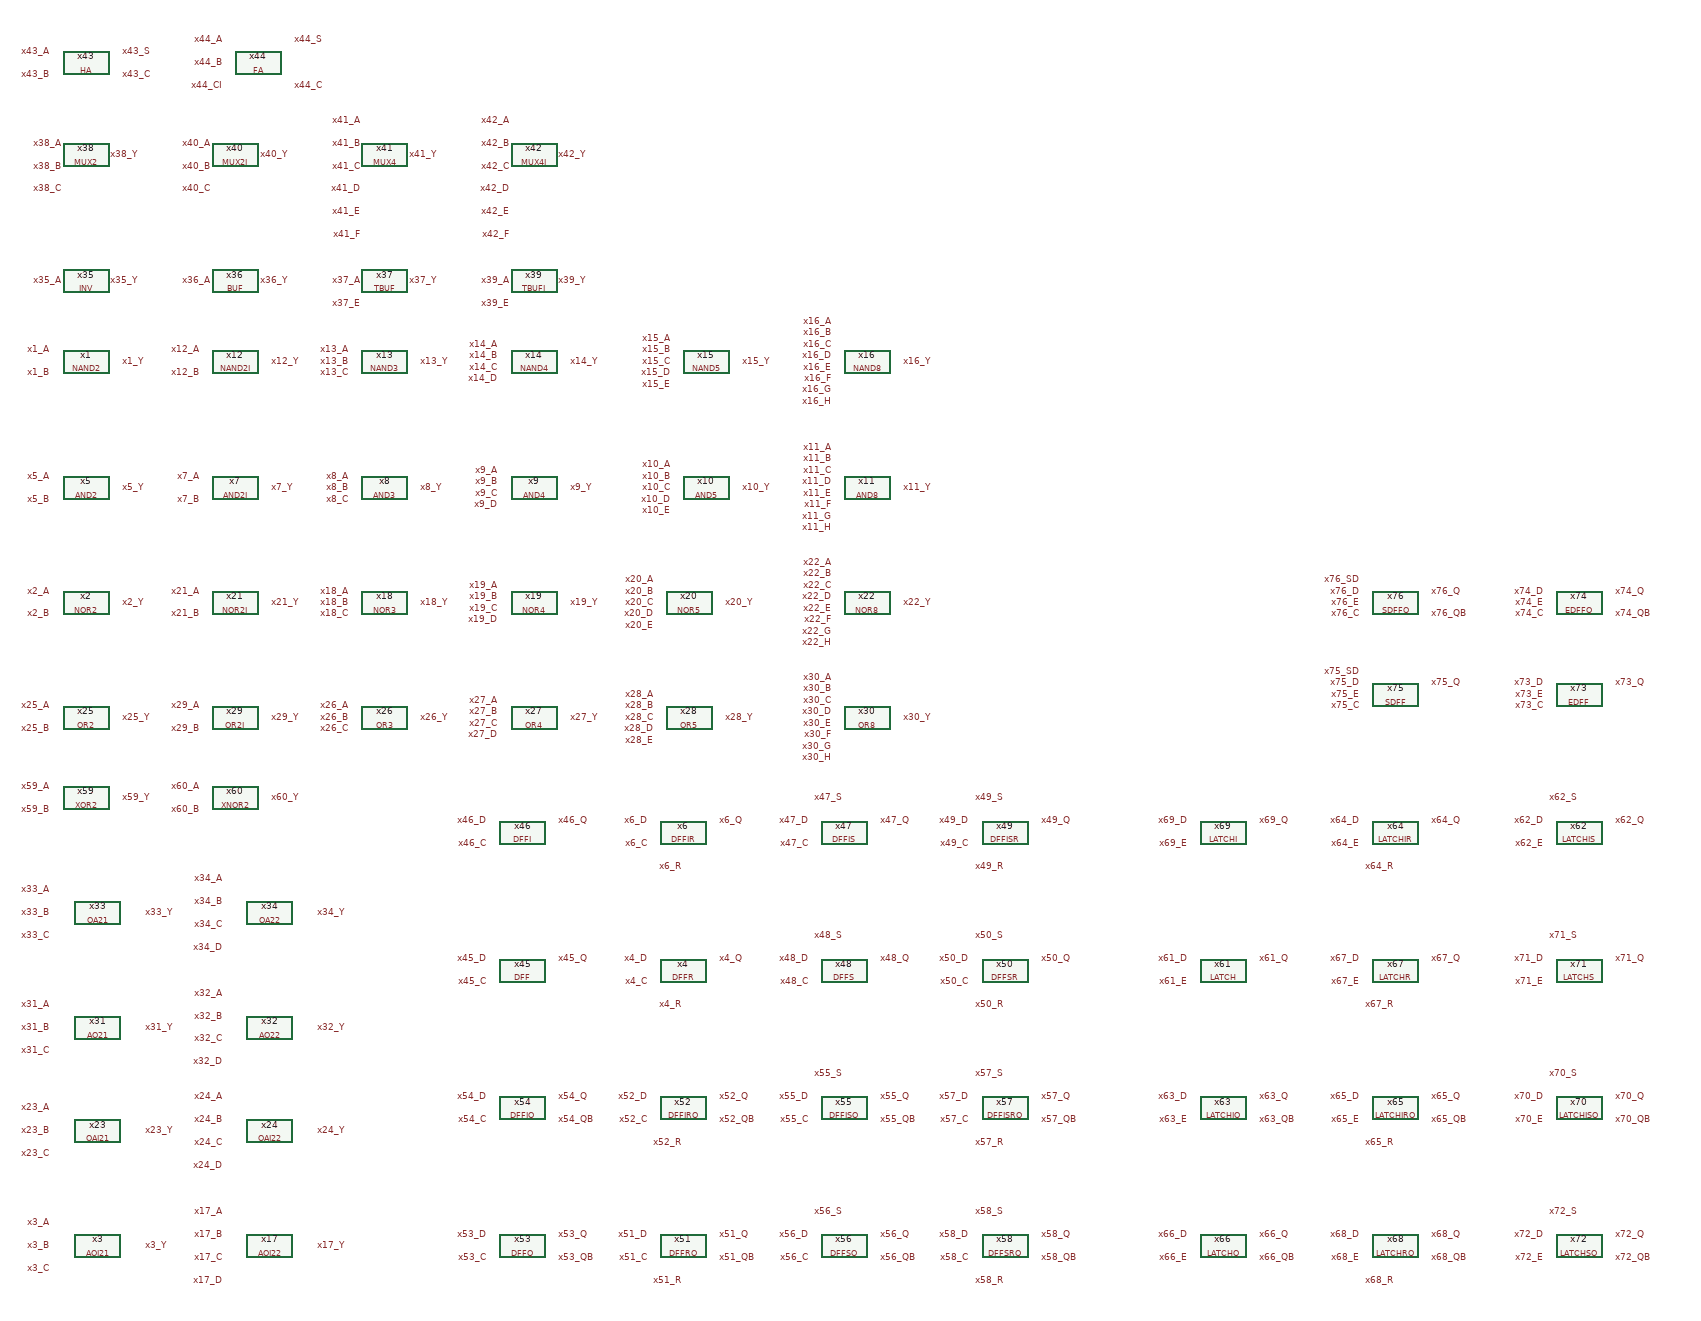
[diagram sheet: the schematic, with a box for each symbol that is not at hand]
v {xschem version=2.9.7 file_version=1.2}
G {}
V {}
S {}
E {}
C {NAND2.sym} 140 -1720 0 0 {name=x1 VCCPIN=VCC VSSPIN=VSS}
C {NOR2.sym} 140 -1300 0 0 {name=x2 VCCPIN=VCC VSSPIN=VSS}
C {AOI21.sym} 160 -180 0 0 {name=x3 VCCPIN=VCC VSSPIN=VSS}
C {DFFR.sym} 1180 -660 0 0 {name=x4 VCCPIN=VCC VSSPIN=VSS}
C {AND2.sym} 140 -1500 0 0 {name=x5 VCCPIN=VCC VSSPIN=VSS}
C {DFFIR.sym} 1180 -900 0 0 {name=x6 VCCPIN=VCC VSSPIN=VSS}
C {AND2I.sym} 400 -1500 0 0 {name=x7 VCCPIN=VCC VSSPIN=VSS}
C {AND3.sym} 660 -1500 0 0 {name=x8 VCCPIN=VCC VSSPIN=VSS}
C {AND4.sym} 920 -1500 0 0 {name=x9 VCCPIN=VCC VSSPIN=VSS}
C {AND5.sym} 1220 -1500 0 0 {name=x10 VCCPIN=VCC VSSPIN=VSS}
C {AND8.sym} 1500 -1500 0 0 {name=x11 VCCPIN=VCC VSSPIN=VSS}
C {NAND2I.sym} 400 -1720 0 0 {name=x12 VCCPIN=VCC VSSPIN=VSS}
C {NAND3.sym} 660 -1720 0 0 {name=x13 VCCPIN=VCC VSSPIN=VSS}
C {NAND4.sym} 920 -1720 0 0 {name=x14 VCCPIN=VCC VSSPIN=VSS}
C {NAND5.sym} 1220 -1720 0 0 {name=x15 VCCPIN=VCC VSSPIN=VSS}
C {NAND8.sym} 1500 -1720 0 0 {name=x16 VCCPIN=VCC VSSPIN=VSS}
C {AOI22.sym} 460 -180 0 0 {name=x17 VCCPIN=VCC VSSPIN=VSS}
C {NOR3.sym} 660 -1300 0 0 {name=x18 VCCPIN=VCC VSSPIN=VSS}
C {NOR4.sym} 920 -1300 0 0 {name=x19 VCCPIN=VCC VSSPIN=VSS}
C {NOR5.sym} 1190 -1300 0 0 {name=x20 VCCPIN=VCC VSSPIN=VSS}
C {NOR2I.sym} 400 -1300 0 0 {name=x21 VCCPIN=VCC VSSPIN=VSS}
C {NOR8.sym} 1500 -1300 0 0 {name=x22 VCCPIN=VCC VSSPIN=VSS}
C {OAI21.sym} 160 -380 0 0 {name=x23 VCCPIN=VCC VSSPIN=VSS}
C {OAI22.sym} 460 -380 0 0 {name=x24 VCCPIN=VCC VSSPIN=VSS}
C {OR2.sym} 140 -1100 0 0 {name=x25 VCCPIN=VCC VSSPIN=VSS}
C {OR3.sym} 660 -1100 0 0 {name=x26 VCCPIN=VCC VSSPIN=VSS}
C {OR4.sym} 920 -1100 0 0 {name=x27 VCCPIN=VCC VSSPIN=VSS}
C {OR5.sym} 1190 -1100 0 0 {name=x28 VCCPIN=VCC VSSPIN=VSS}
C {OR2I.sym} 400 -1100 0 0 {name=x29 VCCPIN=VCC VSSPIN=VSS}
C {OR8.sym} 1500 -1100 0 0 {name=x30 VCCPIN=VCC VSSPIN=VSS}
C {AO21.sym} 160 -560 0 0 {name=x31 VCCPIN=VCC VSSPIN=VSS}
C {AO22.sym} 460 -560 0 0 {name=x32 VCCPIN=VCC VSSPIN=VSS}
C {OA21.sym} 160 -760 0 0 {name=x33 VCCPIN=VCC VSSPIN=VSS}
C {OA22.sym} 460 -760 0 0 {name=x34 VCCPIN=VCC VSSPIN=VSS}
C {INV.sym} 140 -1860 0 0 {name=x35 VCCPIN=VCC VSSPIN=VSS}
C {BUF.sym} 400 -1860 0 0 {name=x36 VCCPIN=VCC VSSPIN=VSS}
C {TBUF.sym} 660 -1860 0 0 {name=x37 VCCPIN=VCC VSSPIN=VSS}
C {TBUFI.sym} 920 -1860 0 0 {name=x39 VCCPIN=VCC VSSPIN=VSS}
C {MUX2.sym} 140 -2080 0 0 {name=x38 VCCPIN=VCC VSSPIN=VSS}
C {MUX2I.sym} 400 -2080 0 0 {name=x40 VCCPIN=VCC VSSPIN=VSS}
C {MUX4.sym} 660 -2080 0 0 {name=x41 VCCPIN=VCC VSSPIN=VSS}
C {MUX4I.sym} 920 -2080 0 0 {name=x42 VCCPIN=VCC VSSPIN=VSS}
C {HA.sym} 140 -2240 0 0 {name=x43 VCCPIN=VCC VSSPIN=VSS}
C {FA.sym} 440 -2240 0 0 {name=x44 VCCPIN=VCC VSSPIN=VSS}
C {DFF.sym} 900 -660 0 0 {name=x45 VCCPIN=VCC VSSPIN=VSS}
C {DFFI.sym} 900 -900 0 0 {name=x46 VCCPIN=VCC VSSPIN=VSS}
C {DFFIS.sym} 1460 -900 0 0 {name=x47 VCCPIN=VCC VSSPIN=VSS}
C {DFFS.sym} 1460 -660 0 0 {name=x48 VCCPIN=VCC VSSPIN=VSS}
C {DFFISR.sym} 1740 -900 0 0 {name=x49 VCCPIN=VCC VSSPIN=VSS}
C {DFFSR.sym} 1740 -660 0 0 {name=x50 VCCPIN=VCC VSSPIN=VSS}
C {DFFRQ.sym} 1180 -180 0 0 {name=x51 VCCPIN=VCC VSSPIN=VSS}
C {DFFIRQ.sym} 1180 -420 0 0 {name=x52 VCCPIN=VCC VSSPIN=VSS}
C {DFFQ.sym} 900 -180 0 0 {name=x53 VCCPIN=VCC VSSPIN=VSS}
C {DFFIQ.sym} 900 -420 0 0 {name=x54 VCCPIN=VCC VSSPIN=VSS}
C {DFFISQ.sym} 1460 -420 0 0 {name=x55 VCCPIN=VCC VSSPIN=VSS}
C {DFFSQ.sym} 1460 -180 0 0 {name=x56 VCCPIN=VCC VSSPIN=VSS}
C {DFFISRQ.sym} 1740 -420 0 0 {name=x57 VCCPIN=VCC VSSPIN=VSS}
C {DFFSRQ.sym} 1740 -180 0 0 {name=x58 VCCPIN=VCC VSSPIN=VSS}
C {XOR2.sym} 140 -960 0 0 {name=x59 VCCPIN=VCC VSSPIN=VSS}
C {XNOR2.sym} 400 -960 0 0 {name=x60 VCCPIN=VCC VSSPIN=VSS}
C {LATCH.sym} 2120 -660 0 0 {name=x61 VCCPIN=VCC VSSPIN=VSS}
C {LATCHIQ.sym} 2120 -420 0 0 {name=x63 VCCPIN=VCC VSSPIN=VSS}
C {LATCHIR.sym} 2420 -900 0 0 {name=x64 VCCPIN=VCC VSSPIN=VSS}
C {LATCHIRQ.sym} 2420 -420 0 0 {name=x65 VCCPIN=VCC VSSPIN=VSS}
C {LATCHQ.sym} 2120 -180 0 0 {name=x66 VCCPIN=VCC VSSPIN=VSS}
C {LATCHR.sym} 2420 -660 0 0 {name=x67 VCCPIN=VCC VSSPIN=VSS}
C {LATCHRQ.sym} 2420 -180 0 0 {name=x68 VCCPIN=VCC VSSPIN=VSS}
C {LATCHI.sym} 2120 -900 0 0 {name=x69 VCCPIN=VCC VSSPIN=VSS}
C {LATCHIS.sym} 2740 -900 0 0 {name=x62 VCCPIN=VCC VSSPIN=VSS}
C {LATCHISQ.sym} 2740 -420 0 0 {name=x70 VCCPIN=VCC VSSPIN=VSS}
C {LATCHS.sym} 2740 -660 0 0 {name=x71 VCCPIN=VCC VSSPIN=VSS}
C {LATCHSQ.sym} 2740 -180 0 0 {name=x72 VCCPIN=VCC VSSPIN=VSS}
C {EDFF.sym} 2740 -1140 0 0 {name=x73 VCCPIN=VCC VSSPIN=VSS}
C {EDFFQ.sym} 2740 -1300 0 0 {name=x74 VCCPIN=VCC VSSPIN=VSS}
C {SDFF.sym} 2420 -1140 0 0 {name=x75 VCCPIN=VCC VSSPIN=VSS}
C {SDFFQ.sym} 2420 -1300 0 0 {name=x76 VCCPIN=VCC VSSPIN=VSS}
C {title.sym} 160 -30 0 0 {name=l1 author="Stefan Schippers"}
C {lab_pin.sym} 200 -1720 0 1 {name=p1 lab=x1_Y}
C {lab_pin.sym} 80 -1740 0 0 {name=p2 lab=x1_A}
C {lab_pin.sym} 80 -1700 0 0 {name=p3 lab=x1_B}
C {lab_pin.sym} 200 -1300 0 1 {name=p4 lab=x2_Y}
C {lab_pin.sym} 80 -1320 0 0 {name=p5 lab=x2_A}
C {lab_pin.sym} 80 -1280 0 0 {name=p6 lab=x2_B}
C {lab_pin.sym} 240 -180 0 1 {name=p7 lab=x3_Y}
C {lab_pin.sym} 80 -220 0 0 {name=p8 lab=x3_A}
C {lab_pin.sym} 80 -180 0 0 {name=p9 lab=x3_B}
C {lab_pin.sym} 80 -140 0 0 {name=p10 lab=x3_C}
C {lab_pin.sym} 1240 -680 0 1 {name=p11 lab=x4_Q}
C {lab_pin.sym} 1120 -680 0 0 {name=p12 lab=x4_D}
C {lab_pin.sym} 1120 -640 0 0 {name=p13 lab=x4_C}
C {lab_pin.sym} 1180 -600 0 0 {name=p14 lab=x4_R}
C {lab_pin.sym} 200 -1500 0 1 {name=p15 lab=x5_Y}
C {lab_pin.sym} 80 -1520 0 0 {name=p16 lab=x5_A}
C {lab_pin.sym} 80 -1480 0 0 {name=p17 lab=x5_B}
C {lab_pin.sym} 1240 -920 0 1 {name=p18 lab=x6_Q}
C {lab_pin.sym} 1120 -920 0 0 {name=p19 lab=x6_D}
C {lab_pin.sym} 1120 -880 0 0 {name=p20 lab=x6_C}
C {lab_pin.sym} 1180 -840 0 0 {name=p21 lab=x6_R}
C {lab_pin.sym} 460 -1500 0 1 {name=p22 lab=x7_Y}
C {lab_pin.sym} 340 -1520 0 0 {name=p23 lab=x7_A}
C {lab_pin.sym} 340 -1480 0 0 {name=p24 lab=x7_B}
C {lab_pin.sym} 720 -1500 0 1 {name=p25 lab=x8_Y}
C {lab_pin.sym} 600 -1520 0 0 {name=p26 lab=x8_A}
C {lab_pin.sym} 600 -1500 0 0 {name=p27 lab=x8_B}
C {lab_pin.sym} 600 -1480 0 0 {name=p28 lab=x8_C}
C {lab_pin.sym} 980 -1500 0 1 {name=p29 lab=x9_Y}
C {lab_pin.sym} 860 -1530 0 0 {name=p30 lab=x9_A}
C {lab_pin.sym} 860 -1510 0 0 {name=p31 lab=x9_B}
C {lab_pin.sym} 860 -1490 0 0 {name=p32 lab=x9_C}
C {lab_pin.sym} 860 -1470 0 0 {name=p33 lab=x9_D}
C {lab_pin.sym} 1280 -1500 0 1 {name=p34 lab=x10_Y}
C {lab_pin.sym} 1160 -1540 0 0 {name=p35 lab=x10_A}
C {lab_pin.sym} 1160 -1520 0 0 {name=p36 lab=x10_B}
C {lab_pin.sym} 1160 -1500 0 0 {name=p37 lab=x10_C}
C {lab_pin.sym} 1160 -1480 0 0 {name=p38 lab=x10_D}
C {lab_pin.sym} 1160 -1460 0 0 {name=p39 lab=x10_E}
C {lab_pin.sym} 1560 -1500 0 1 {name=p40 lab=x11_Y}
C {lab_pin.sym} 1440 -1570 0 0 {name=p41 lab=x11_A}
C {lab_pin.sym} 1440 -1550 0 0 {name=p42 lab=x11_B}
C {lab_pin.sym} 1440 -1530 0 0 {name=p43 lab=x11_C}
C {lab_pin.sym} 1440 -1510 0 0 {name=p44 lab=x11_D}
C {lab_pin.sym} 1440 -1490 0 0 {name=p45 lab=x11_E}
C {lab_pin.sym} 1440 -1470 0 0 {name=p46 lab=x11_F}
C {lab_pin.sym} 1440 -1450 0 0 {name=p47 lab=x11_G}
C {lab_pin.sym} 1440 -1430 0 0 {name=p48 lab=x11_H}
C {lab_pin.sym} 460 -1720 0 1 {name=p49 lab=x12_Y}
C {lab_pin.sym} 340 -1740 0 0 {name=p50 lab=x12_A}
C {lab_pin.sym} 340 -1700 0 0 {name=p51 lab=x12_B}
C {lab_pin.sym} 720 -1720 0 1 {name=p52 lab=x13_Y}
C {lab_pin.sym} 600 -1740 0 0 {name=p53 lab=x13_A}
C {lab_pin.sym} 600 -1720 0 0 {name=p54 lab=x13_B}
C {lab_pin.sym} 600 -1700 0 0 {name=p55 lab=x13_C}
C {lab_pin.sym} 980 -1720 0 1 {name=p56 lab=x14_Y}
C {lab_pin.sym} 860 -1750 0 0 {name=p57 lab=x14_A}
C {lab_pin.sym} 860 -1730 0 0 {name=p58 lab=x14_B}
C {lab_pin.sym} 860 -1710 0 0 {name=p59 lab=x14_C}
C {lab_pin.sym} 860 -1690 0 0 {name=p60 lab=x14_D}
C {lab_pin.sym} 1280 -1720 0 1 {name=p61 lab=x15_Y}
C {lab_pin.sym} 1160 -1760 0 0 {name=p62 lab=x15_A}
C {lab_pin.sym} 1160 -1740 0 0 {name=p63 lab=x15_B}
C {lab_pin.sym} 1160 -1720 0 0 {name=p64 lab=x15_C}
C {lab_pin.sym} 1160 -1700 0 0 {name=p65 lab=x15_D}
C {lab_pin.sym} 1160 -1680 0 0 {name=p66 lab=x15_E}
C {lab_pin.sym} 1560 -1720 0 1 {name=p67 lab=x16_Y}
C {lab_pin.sym} 1440 -1790 0 0 {name=p68 lab=x16_A}
C {lab_pin.sym} 1440 -1770 0 0 {name=p69 lab=x16_B}
C {lab_pin.sym} 1440 -1750 0 0 {name=p70 lab=x16_C}
C {lab_pin.sym} 1440 -1730 0 0 {name=p71 lab=x16_D}
C {lab_pin.sym} 1440 -1710 0 0 {name=p72 lab=x16_E}
C {lab_pin.sym} 1440 -1690 0 0 {name=p73 lab=x16_F}
C {lab_pin.sym} 1440 -1670 0 0 {name=p74 lab=x16_G}
C {lab_pin.sym} 1440 -1650 0 0 {name=p75 lab=x16_H}
C {lab_pin.sym} 540 -180 0 1 {name=p76 lab=x17_Y}
C {lab_pin.sym} 380 -240 0 0 {name=p77 lab=x17_A}
C {lab_pin.sym} 380 -200 0 0 {name=p78 lab=x17_B}
C {lab_pin.sym} 380 -160 0 0 {name=p79 lab=x17_C}
C {lab_pin.sym} 380 -120 0 0 {name=p80 lab=x17_D}
C {lab_pin.sym} 720 -1300 0 1 {name=p81 lab=x18_Y}
C {lab_pin.sym} 600 -1320 0 0 {name=p82 lab=x18_A}
C {lab_pin.sym} 600 -1300 0 0 {name=p83 lab=x18_B}
C {lab_pin.sym} 600 -1280 0 0 {name=p84 lab=x18_C}
C {lab_pin.sym} 980 -1300 0 1 {name=p85 lab=x19_Y}
C {lab_pin.sym} 860 -1330 0 0 {name=p86 lab=x19_A}
C {lab_pin.sym} 860 -1310 0 0 {name=p87 lab=x19_B}
C {lab_pin.sym} 860 -1290 0 0 {name=p88 lab=x19_C}
C {lab_pin.sym} 860 -1270 0 0 {name=p89 lab=x19_D}
C {lab_pin.sym} 1250 -1300 0 1 {name=p90 lab=x20_Y}
C {lab_pin.sym} 1130 -1340 0 0 {name=p91 lab=x20_A}
C {lab_pin.sym} 1130 -1320 0 0 {name=p92 lab=x20_B}
C {lab_pin.sym} 1130 -1300 0 0 {name=p93 lab=x20_C}
C {lab_pin.sym} 1130 -1280 0 0 {name=p94 lab=x20_D}
C {lab_pin.sym} 1130 -1260 0 0 {name=p95 lab=x20_E}
C {lab_pin.sym} 460 -1300 0 1 {name=p96 lab=x21_Y}
C {lab_pin.sym} 340 -1320 0 0 {name=p97 lab=x21_A}
C {lab_pin.sym} 340 -1280 0 0 {name=p98 lab=x21_B}
C {lab_pin.sym} 1560 -1300 0 1 {name=p99 lab=x22_Y}
C {lab_pin.sym} 1440 -1370 0 0 {name=p100 lab=x22_A}
C {lab_pin.sym} 1440 -1350 0 0 {name=p101 lab=x22_B}
C {lab_pin.sym} 1440 -1330 0 0 {name=p102 lab=x22_C}
C {lab_pin.sym} 1440 -1310 0 0 {name=p103 lab=x22_D}
C {lab_pin.sym} 1440 -1290 0 0 {name=p104 lab=x22_E}
C {lab_pin.sym} 1440 -1270 0 0 {name=p105 lab=x22_F}
C {lab_pin.sym} 1440 -1250 0 0 {name=p106 lab=x22_G}
C {lab_pin.sym} 1440 -1230 0 0 {name=p107 lab=x22_H}
C {lab_pin.sym} 240 -380 0 1 {name=p108 lab=x23_Y}
C {lab_pin.sym} 80 -420 0 0 {name=p109 lab=x23_A}
C {lab_pin.sym} 80 -380 0 0 {name=p110 lab=x23_B}
C {lab_pin.sym} 80 -340 0 0 {name=p111 lab=x23_C}
C {lab_pin.sym} 540 -380 0 1 {name=p112 lab=x24_Y}
C {lab_pin.sym} 380 -440 0 0 {name=p113 lab=x24_A}
C {lab_pin.sym} 380 -400 0 0 {name=p114 lab=x24_B}
C {lab_pin.sym} 380 -360 0 0 {name=p115 lab=x24_C}
C {lab_pin.sym} 380 -320 0 0 {name=p116 lab=x24_D}
C {lab_pin.sym} 200 -1100 0 1 {name=p117 lab=x25_Y}
C {lab_pin.sym} 80 -1120 0 0 {name=p118 lab=x25_A}
C {lab_pin.sym} 80 -1080 0 0 {name=p119 lab=x25_B}
C {lab_pin.sym} 720 -1100 0 1 {name=p120 lab=x26_Y}
C {lab_pin.sym} 600 -1120 0 0 {name=p121 lab=x26_A}
C {lab_pin.sym} 600 -1100 0 0 {name=p122 lab=x26_B}
C {lab_pin.sym} 600 -1080 0 0 {name=p123 lab=x26_C}
C {lab_pin.sym} 980 -1100 0 1 {name=p124 lab=x27_Y}
C {lab_pin.sym} 860 -1130 0 0 {name=p125 lab=x27_A}
C {lab_pin.sym} 860 -1110 0 0 {name=p126 lab=x27_B}
C {lab_pin.sym} 860 -1090 0 0 {name=p127 lab=x27_C}
C {lab_pin.sym} 860 -1070 0 0 {name=p128 lab=x27_D}
C {lab_pin.sym} 1250 -1100 0 1 {name=p129 lab=x28_Y}
C {lab_pin.sym} 1130 -1140 0 0 {name=p130 lab=x28_A}
C {lab_pin.sym} 1130 -1120 0 0 {name=p131 lab=x28_B}
C {lab_pin.sym} 1130 -1100 0 0 {name=p132 lab=x28_C}
C {lab_pin.sym} 1130 -1080 0 0 {name=p133 lab=x28_D}
C {lab_pin.sym} 1130 -1060 0 0 {name=p134 lab=x28_E}
C {lab_pin.sym} 460 -1100 0 1 {name=p135 lab=x29_Y}
C {lab_pin.sym} 340 -1120 0 0 {name=p136 lab=x29_A}
C {lab_pin.sym} 340 -1080 0 0 {name=p137 lab=x29_B}
C {lab_pin.sym} 1560 -1100 0 1 {name=p138 lab=x30_Y}
C {lab_pin.sym} 1440 -1170 0 0 {name=p139 lab=x30_A}
C {lab_pin.sym} 1440 -1150 0 0 {name=p140 lab=x30_B}
C {lab_pin.sym} 1440 -1130 0 0 {name=p141 lab=x30_C}
C {lab_pin.sym} 1440 -1110 0 0 {name=p142 lab=x30_D}
C {lab_pin.sym} 1440 -1090 0 0 {name=p143 lab=x30_E}
C {lab_pin.sym} 1440 -1070 0 0 {name=p144 lab=x30_F}
C {lab_pin.sym} 1440 -1050 0 0 {name=p145 lab=x30_G}
C {lab_pin.sym} 1440 -1030 0 0 {name=p146 lab=x30_H}
C {lab_pin.sym} 240 -560 0 1 {name=p147 lab=x31_Y}
C {lab_pin.sym} 80 -600 0 0 {name=p148 lab=x31_A}
C {lab_pin.sym} 80 -560 0 0 {name=p149 lab=x31_B}
C {lab_pin.sym} 80 -520 0 0 {name=p150 lab=x31_C}
C {lab_pin.sym} 540 -560 0 1 {name=p151 lab=x32_Y}
C {lab_pin.sym} 380 -620 0 0 {name=p152 lab=x32_A}
C {lab_pin.sym} 380 -580 0 0 {name=p153 lab=x32_B}
C {lab_pin.sym} 380 -540 0 0 {name=p154 lab=x32_C}
C {lab_pin.sym} 380 -500 0 0 {name=p155 lab=x32_D}
C {lab_pin.sym} 240 -760 0 1 {name=p156 lab=x33_Y}
C {lab_pin.sym} 80 -800 0 0 {name=p157 lab=x33_A}
C {lab_pin.sym} 80 -760 0 0 {name=p158 lab=x33_B}
C {lab_pin.sym} 80 -720 0 0 {name=p159 lab=x33_C}
C {lab_pin.sym} 540 -760 0 1 {name=p160 lab=x34_Y}
C {lab_pin.sym} 380 -820 0 0 {name=p161 lab=x34_A}
C {lab_pin.sym} 380 -780 0 0 {name=p162 lab=x34_B}
C {lab_pin.sym} 380 -740 0 0 {name=p163 lab=x34_C}
C {lab_pin.sym} 380 -700 0 0 {name=p164 lab=x34_D}
C {lab_pin.sym} 180 -1860 0 1 {name=p165 lab=x35_Y}
C {lab_pin.sym} 100 -1860 0 0 {name=p166 lab=x35_A}
C {lab_pin.sym} 440 -1860 0 1 {name=p167 lab=x36_Y}
C {lab_pin.sym} 360 -1860 0 0 {name=p168 lab=x36_A}
C {lab_pin.sym} 700 -1860 0 1 {name=p169 lab=x37_Y}
C {lab_pin.sym} 620 -1860 0 0 {name=p170 lab=x37_A}
C {lab_pin.sym} 620 -1820 0 0 {name=p171 lab=x37_E}
C {lab_pin.sym} 960 -1860 0 1 {name=p172 lab=x39_Y}
C {lab_pin.sym} 880 -1860 0 0 {name=p173 lab=x39_A}
C {lab_pin.sym} 880 -1820 0 0 {name=p174 lab=x39_E}
C {lab_pin.sym} 180 -2080 0 1 {name=p175 lab=x38_Y}
C {lab_pin.sym} 100 -2100 0 0 {name=p176 lab=x38_A}
C {lab_pin.sym} 100 -2060 0 0 {name=p177 lab=x38_B}
C {lab_pin.sym} 100 -2020 0 0 {name=p178 lab=x38_C}
C {lab_pin.sym} 440 -2080 0 1 {name=p179 lab=x40_Y}
C {lab_pin.sym} 360 -2100 0 0 {name=p180 lab=x40_A}
C {lab_pin.sym} 360 -2060 0 0 {name=p181 lab=x40_B}
C {lab_pin.sym} 360 -2020 0 0 {name=p182 lab=x40_C}
C {lab_pin.sym} 700 -2080 0 1 {name=p183 lab=x41_Y}
C {lab_pin.sym} 620 -2140 0 0 {name=p184 lab=x41_A}
C {lab_pin.sym} 620 -2100 0 0 {name=p185 lab=x41_B}
C {lab_pin.sym} 620 -2060 0 0 {name=p186 lab=x41_C}
C {lab_pin.sym} 620 -2020 0 0 {name=p187 lab=x41_D}
C {lab_pin.sym} 620 -1980 0 0 {name=p188 lab=x41_E}
C {lab_pin.sym} 620 -1940 0 0 {name=p189 lab=x41_F}
C {lab_pin.sym} 960 -2080 0 1 {name=p190 lab=x42_Y}
C {lab_pin.sym} 880 -2140 0 0 {name=p191 lab=x42_A}
C {lab_pin.sym} 880 -2100 0 0 {name=p192 lab=x42_B}
C {lab_pin.sym} 880 -2060 0 0 {name=p193 lab=x42_C}
C {lab_pin.sym} 880 -2020 0 0 {name=p194 lab=x42_D}
C {lab_pin.sym} 880 -1980 0 0 {name=p195 lab=x42_E}
C {lab_pin.sym} 880 -1940 0 0 {name=p196 lab=x42_F}
C {lab_pin.sym} 200 -2260 0 1 {name=p197 lab=x43_S}
C {lab_pin.sym} 200 -2220 0 1 {name=p198 lab=x43_C}
C {lab_pin.sym} 80 -2260 0 0 {name=p199 lab=x43_A}
C {lab_pin.sym} 80 -2220 0 0 {name=p200 lab=x43_B}
C {lab_pin.sym} 500 -2280 0 1 {name=p201 lab=x44_S}
C {lab_pin.sym} 500 -2200 0 1 {name=p202 lab=x44_C}
C {lab_pin.sym} 380 -2280 0 0 {name=p203 lab=x44_A}
C {lab_pin.sym} 380 -2240 0 0 {name=p204 lab=x44_B}
C {lab_pin.sym} 380 -2200 0 0 {name=p205 lab=x44_CI}
C {lab_pin.sym} 960 -680 0 1 {name=p206 lab=x45_Q}
C {lab_pin.sym} 840 -680 0 0 {name=p207 lab=x45_D}
C {lab_pin.sym} 840 -640 0 0 {name=p208 lab=x45_C}
C {lab_pin.sym} 960 -920 0 1 {name=p209 lab=x46_Q}
C {lab_pin.sym} 840 -920 0 0 {name=p210 lab=x46_D}
C {lab_pin.sym} 840 -880 0 0 {name=p211 lab=x46_C}
C {lab_pin.sym} 1520 -920 0 1 {name=p212 lab=x47_Q}
C {lab_pin.sym} 1400 -920 0 0 {name=p213 lab=x47_D}
C {lab_pin.sym} 1400 -880 0 0 {name=p214 lab=x47_C}
C {lab_pin.sym} 1460 -960 0 0 {name=p215 lab=x47_S}
C {lab_pin.sym} 1520 -680 0 1 {name=p216 lab=x48_Q}
C {lab_pin.sym} 1400 -680 0 0 {name=p217 lab=x48_D}
C {lab_pin.sym} 1400 -640 0 0 {name=p218 lab=x48_C}
C {lab_pin.sym} 1460 -720 0 0 {name=p219 lab=x48_S}
C {lab_pin.sym} 1800 -920 0 1 {name=p220 lab=x49_Q}
C {lab_pin.sym} 1680 -920 0 0 {name=p221 lab=x49_D}
C {lab_pin.sym} 1680 -880 0 0 {name=p222 lab=x49_C}
C {lab_pin.sym} 1740 -960 0 0 {name=p223 lab=x49_S}
C {lab_pin.sym} 1740 -840 0 0 {name=p224 lab=x49_R}
C {lab_pin.sym} 1800 -680 0 1 {name=p225 lab=x50_Q}
C {lab_pin.sym} 1680 -680 0 0 {name=p226 lab=x50_D}
C {lab_pin.sym} 1680 -640 0 0 {name=p227 lab=x50_C}
C {lab_pin.sym} 1740 -720 0 0 {name=p228 lab=x50_S}
C {lab_pin.sym} 1740 -600 0 0 {name=p229 lab=x50_R}
C {lab_pin.sym} 1240 -200 0 1 {name=p230 lab=x51_Q}
C {lab_pin.sym} 1240 -160 0 1 {name=p231 lab=x51_QB}
C {lab_pin.sym} 1120 -200 0 0 {name=p232 lab=x51_D}
C {lab_pin.sym} 1120 -160 0 0 {name=p233 lab=x51_C}
C {lab_pin.sym} 1180 -120 0 0 {name=p234 lab=x51_R}
C {lab_pin.sym} 1240 -440 0 1 {name=p235 lab=x52_Q}
C {lab_pin.sym} 1240 -400 0 1 {name=p236 lab=x52_QB}
C {lab_pin.sym} 1120 -440 0 0 {name=p237 lab=x52_D}
C {lab_pin.sym} 1120 -400 0 0 {name=p238 lab=x52_C}
C {lab_pin.sym} 1180 -360 0 0 {name=p239 lab=x52_R}
C {lab_pin.sym} 960 -200 0 1 {name=p240 lab=x53_Q}
C {lab_pin.sym} 960 -160 0 1 {name=p241 lab=x53_QB}
C {lab_pin.sym} 840 -200 0 0 {name=p242 lab=x53_D}
C {lab_pin.sym} 840 -160 0 0 {name=p243 lab=x53_C}
C {lab_pin.sym} 960 -440 0 1 {name=p244 lab=x54_Q}
C {lab_pin.sym} 960 -400 0 1 {name=p245 lab=x54_QB}
C {lab_pin.sym} 840 -440 0 0 {name=p246 lab=x54_D}
C {lab_pin.sym} 840 -400 0 0 {name=p247 lab=x54_C}
C {lab_pin.sym} 1520 -440 0 1 {name=p248 lab=x55_Q}
C {lab_pin.sym} 1520 -400 0 1 {name=p249 lab=x55_QB}
C {lab_pin.sym} 1400 -440 0 0 {name=p250 lab=x55_D}
C {lab_pin.sym} 1400 -400 0 0 {name=p251 lab=x55_C}
C {lab_pin.sym} 1460 -480 0 0 {name=p252 lab=x55_S}
C {lab_pin.sym} 1520 -200 0 1 {name=p253 lab=x56_Q}
C {lab_pin.sym} 1520 -160 0 1 {name=p254 lab=x56_QB}
C {lab_pin.sym} 1400 -200 0 0 {name=p255 lab=x56_D}
C {lab_pin.sym} 1400 -160 0 0 {name=p256 lab=x56_C}
C {lab_pin.sym} 1460 -240 0 0 {name=p257 lab=x56_S}
C {lab_pin.sym} 1800 -440 0 1 {name=p258 lab=x57_Q}
C {lab_pin.sym} 1800 -400 0 1 {name=p259 lab=x57_QB}
C {lab_pin.sym} 1680 -440 0 0 {name=p260 lab=x57_D}
C {lab_pin.sym} 1680 -400 0 0 {name=p261 lab=x57_C}
C {lab_pin.sym} 1740 -480 0 0 {name=p262 lab=x57_S}
C {lab_pin.sym} 1740 -360 0 0 {name=p263 lab=x57_R}
C {lab_pin.sym} 1800 -200 0 1 {name=p264 lab=x58_Q}
C {lab_pin.sym} 1800 -160 0 1 {name=p265 lab=x58_QB}
C {lab_pin.sym} 1680 -200 0 0 {name=p266 lab=x58_D}
C {lab_pin.sym} 1680 -160 0 0 {name=p267 lab=x58_C}
C {lab_pin.sym} 1740 -240 0 0 {name=p268 lab=x58_S}
C {lab_pin.sym} 1740 -120 0 0 {name=p269 lab=x58_R}
C {lab_pin.sym} 200 -960 0 1 {name=p270 lab=x59_Y}
C {lab_pin.sym} 80 -980 0 0 {name=p271 lab=x59_A}
C {lab_pin.sym} 80 -940 0 0 {name=p272 lab=x59_B}
C {lab_pin.sym} 460 -960 0 1 {name=p273 lab=x60_Y}
C {lab_pin.sym} 340 -980 0 0 {name=p274 lab=x60_A}
C {lab_pin.sym} 340 -940 0 0 {name=p275 lab=x60_B}
C {lab_pin.sym} 2180 -680 0 1 {name=p276 lab=x61_Q}
C {lab_pin.sym} 2060 -680 0 0 {name=p277 lab=x61_D}
C {lab_pin.sym} 2060 -640 0 0 {name=p278 lab=x61_E}
C {lab_pin.sym} 2180 -440 0 1 {name=p279 lab=x63_Q}
C {lab_pin.sym} 2180 -400 0 1 {name=p280 lab=x63_QB}
C {lab_pin.sym} 2060 -440 0 0 {name=p281 lab=x63_D}
C {lab_pin.sym} 2060 -400 0 0 {name=p282 lab=x63_E}
C {lab_pin.sym} 2480 -920 0 1 {name=p283 lab=x64_Q}
C {lab_pin.sym} 2360 -920 0 0 {name=p284 lab=x64_D}
C {lab_pin.sym} 2360 -880 0 0 {name=p285 lab=x64_E}
C {lab_pin.sym} 2420 -840 0 0 {name=p286 lab=x64_R}
C {lab_pin.sym} 2480 -440 0 1 {name=p287 lab=x65_Q}
C {lab_pin.sym} 2480 -400 0 1 {name=p288 lab=x65_QB}
C {lab_pin.sym} 2360 -440 0 0 {name=p289 lab=x65_D}
C {lab_pin.sym} 2360 -400 0 0 {name=p290 lab=x65_E}
C {lab_pin.sym} 2420 -360 0 0 {name=p291 lab=x65_R}
C {lab_pin.sym} 2180 -200 0 1 {name=p292 lab=x66_Q}
C {lab_pin.sym} 2180 -160 0 1 {name=p293 lab=x66_QB}
C {lab_pin.sym} 2060 -200 0 0 {name=p294 lab=x66_D}
C {lab_pin.sym} 2060 -160 0 0 {name=p295 lab=x66_E}
C {lab_pin.sym} 2480 -680 0 1 {name=p296 lab=x67_Q}
C {lab_pin.sym} 2360 -680 0 0 {name=p297 lab=x67_D}
C {lab_pin.sym} 2360 -640 0 0 {name=p298 lab=x67_E}
C {lab_pin.sym} 2420 -600 0 0 {name=p299 lab=x67_R}
C {lab_pin.sym} 2480 -200 0 1 {name=p300 lab=x68_Q}
C {lab_pin.sym} 2480 -160 0 1 {name=p301 lab=x68_QB}
C {lab_pin.sym} 2360 -200 0 0 {name=p302 lab=x68_D}
C {lab_pin.sym} 2360 -160 0 0 {name=p303 lab=x68_E}
C {lab_pin.sym} 2420 -120 0 0 {name=p304 lab=x68_R}
C {lab_pin.sym} 2180 -920 0 1 {name=p305 lab=x69_Q}
C {lab_pin.sym} 2060 -920 0 0 {name=p306 lab=x69_D}
C {lab_pin.sym} 2060 -880 0 0 {name=p307 lab=x69_E}
C {lab_pin.sym} 2800 -920 0 1 {name=p308 lab=x62_Q}
C {lab_pin.sym} 2680 -920 0 0 {name=p309 lab=x62_D}
C {lab_pin.sym} 2680 -880 0 0 {name=p310 lab=x62_E}
C {lab_pin.sym} 2740 -960 0 0 {name=p311 lab=x62_S}
C {lab_pin.sym} 2800 -440 0 1 {name=p312 lab=x70_Q}
C {lab_pin.sym} 2800 -400 0 1 {name=p313 lab=x70_QB}
C {lab_pin.sym} 2680 -440 0 0 {name=p314 lab=x70_D}
C {lab_pin.sym} 2680 -400 0 0 {name=p315 lab=x70_E}
C {lab_pin.sym} 2740 -480 0 0 {name=p316 lab=x70_S}
C {lab_pin.sym} 2800 -680 0 1 {name=p317 lab=x71_Q}
C {lab_pin.sym} 2680 -680 0 0 {name=p318 lab=x71_D}
C {lab_pin.sym} 2680 -640 0 0 {name=p319 lab=x71_E}
C {lab_pin.sym} 2740 -720 0 0 {name=p320 lab=x71_S}
C {lab_pin.sym} 2800 -200 0 1 {name=p321 lab=x72_Q}
C {lab_pin.sym} 2800 -160 0 1 {name=p322 lab=x72_QB}
C {lab_pin.sym} 2680 -200 0 0 {name=p323 lab=x72_D}
C {lab_pin.sym} 2680 -160 0 0 {name=p324 lab=x72_E}
C {lab_pin.sym} 2740 -240 0 0 {name=p325 lab=x72_S}
C {lab_pin.sym} 2800 -1160 0 1 {name=p326 lab=x73_Q}
C {lab_pin.sym} 2680 -1160 0 0 {name=p327 lab=x73_D}
C {lab_pin.sym} 2680 -1140 0 0 {name=p328 lab=x73_E}
C {lab_pin.sym} 2680 -1120 0 0 {name=p329 lab=x73_C}
C {lab_pin.sym} 2800 -1320 0 1 {name=p330 lab=x74_Q}
C {lab_pin.sym} 2800 -1280 0 1 {name=p331 lab=x74_QB}
C {lab_pin.sym} 2680 -1320 0 0 {name=p332 lab=x74_D}
C {lab_pin.sym} 2680 -1300 0 0 {name=p333 lab=x74_E}
C {lab_pin.sym} 2680 -1280 0 0 {name=p334 lab=x74_C}
C {lab_pin.sym} 2480 -1160 0 1 {name=p335 lab=x75_Q}
C {lab_pin.sym} 2360 -1180 0 0 {name=p336 lab=x75_SD}
C {lab_pin.sym} 2360 -1160 0 0 {name=p337 lab=x75_D}
C {lab_pin.sym} 2360 -1140 0 0 {name=p338 lab=x75_E}
C {lab_pin.sym} 2360 -1120 0 0 {name=p339 lab=x75_C}
C {lab_pin.sym} 2480 -1320 0 1 {name=p340 lab=x76_Q}
C {lab_pin.sym} 2480 -1280 0 1 {name=p341 lab=x76_QB}
C {lab_pin.sym} 2360 -1340 0 0 {name=p342 lab=x76_SD}
C {lab_pin.sym} 2360 -1320 0 0 {name=p343 lab=x76_D}
C {lab_pin.sym} 2360 -1300 0 0 {name=p344 lab=x76_E}
C {lab_pin.sym} 2360 -1280 0 0 {name=p345 lab=x76_C}
